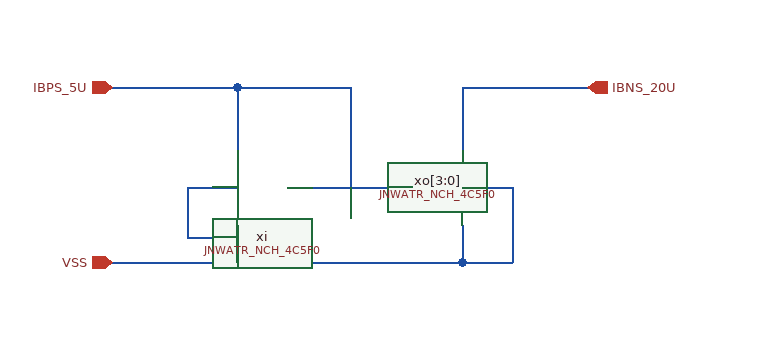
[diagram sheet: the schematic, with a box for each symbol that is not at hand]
v {xschem version=3.4.6 file_version=1.2}
G {}
K {}
V {}
S {}
E {}
N 40 0 70 -0 {lab=IBPS_5U}
N 70 0 140 0 {lab=IBPS_5U}
N 0 -70 0 -30 {lab=IBPS_5U}
N 180 -80 180 -30 {lab=IBNS_20U}
N -0 -80 -0 -70 {lab=IBPS_5U}
N 180 0 220 0 {lab=xxx}
N 220 0 220 30 {lab=xxx}
N -40 0 -40 30 {lab=xxx}
N -40 0 0 0 {lab=xxx}
N 90 -80 90 0 {lab=IBPS_5U}
N 0 -80 90 -80 {lab=IBPS_5U}
N -100 -80 0 -80 {lab=IBPS_5U}
N 180 -80 280 -80 {lab=IBNS_20U}
N 180 30 180 60 {lab=xxx}
N -100 60 180 60 {lab=xxx}
N -0 30 0 60 {lab=xxx}
N -40 30 -40 40 {lab=xxx}
N -40 40 -0 40 {lab=xxx}
N 220 30 220 40 {lab=xxx}
N 180 60 210 60 {lab=xxx}
N 220 40 220 60 {lab=xxx}
N 210 60 220 60 {lab=xxx}
C {JNW_ATR_SKY130A/JNWATR_NCH_4C5F0.sym} 40 0 0 1 {name=xi }
C {JNW_ATR_SKY130A/JNWATR_NCH_4C5F0.sym} 140 0 0 0 {name=xo[3:0] }
C {devices/ipin.sym} -100 -80 0 0 {name=p1 lab=IBPS_5U}
C {devices/ipin.sym} -100 60 0 0 {name=p2 lab=VSS}
C {devices/opin.sym} 280 -80 0 0 {name=p3 lab=IBNS_20U}
